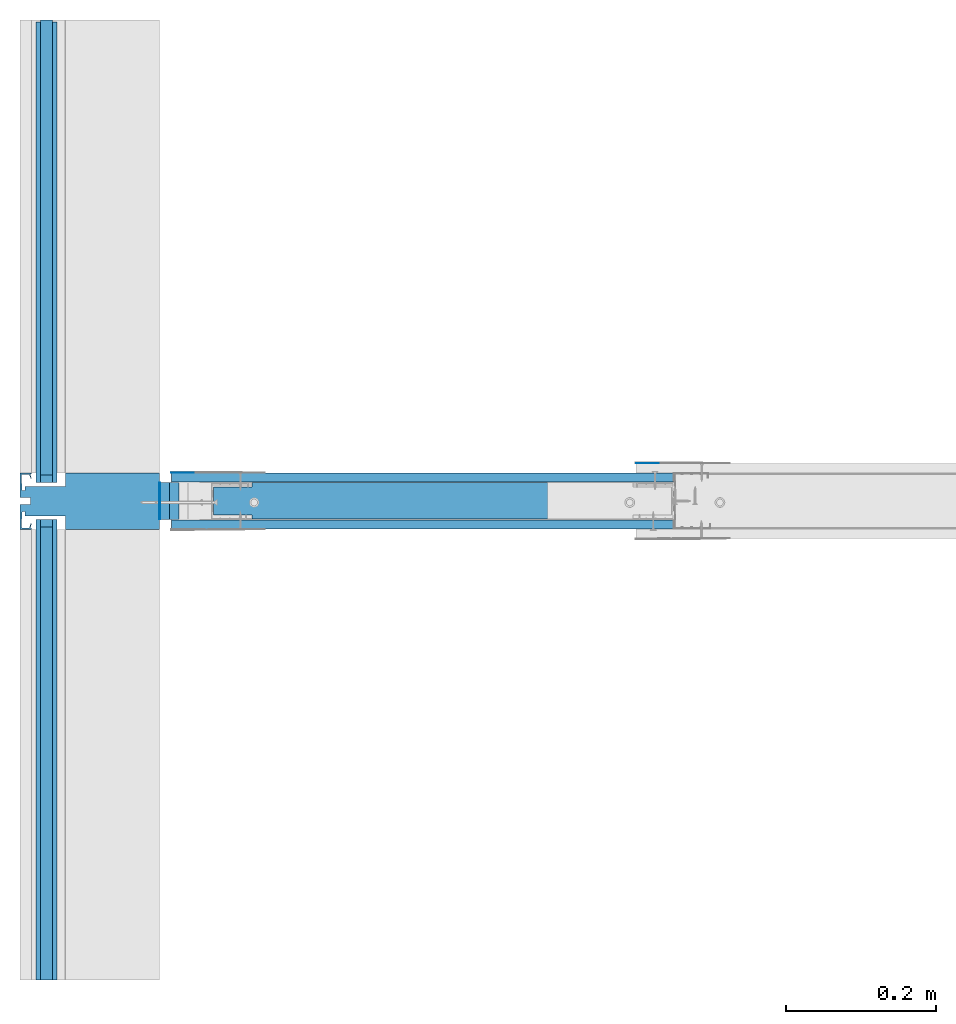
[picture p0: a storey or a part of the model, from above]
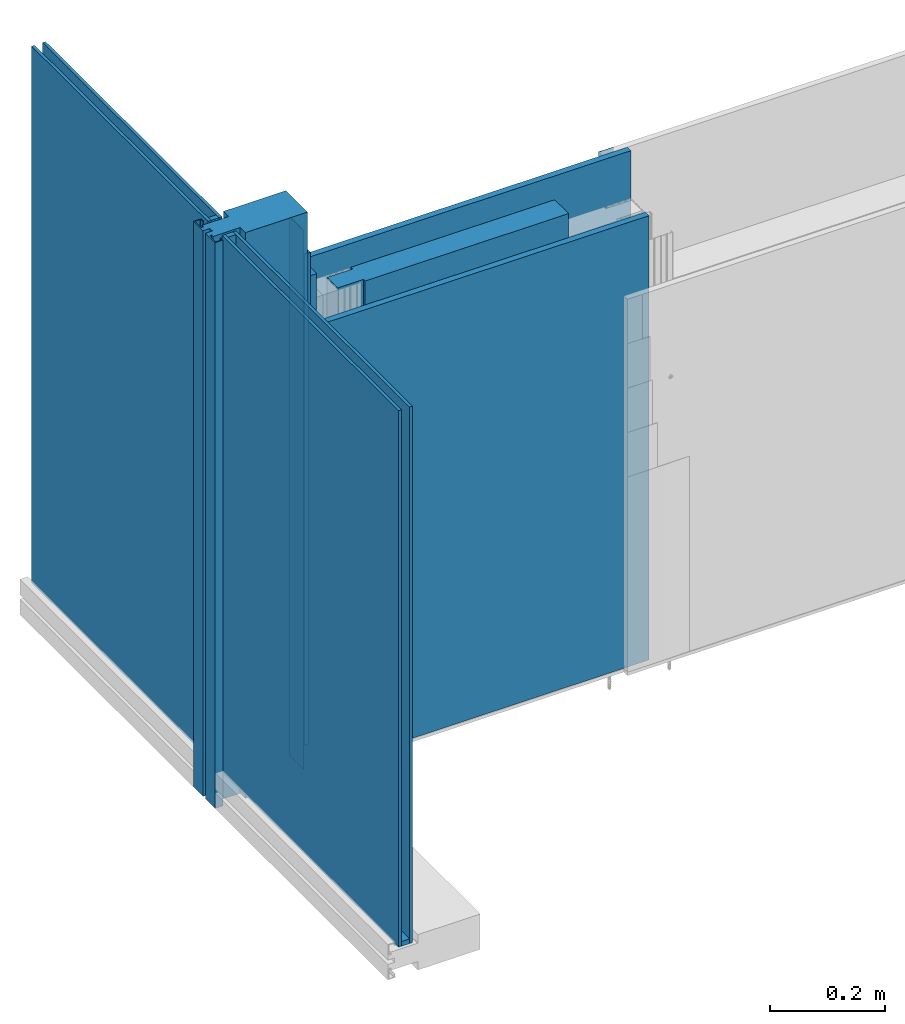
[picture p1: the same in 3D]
Properties of the parts of a building model (IFC2X3)

# File
Description: ViewDefinition [CoordinationView]
Time: 2022-01-05T15:09:06
Made in: SketchUp Pro 2015

# IfcProject, Default Project
Description: Description of Default Project

# IfcSite, Default Site
Description: Description of Default Site; RefLatitude: 24, 28, 0; RefLongitude: 54, 25, 0; RefElevation: 10 mm

# IfcBuilding, Default Building
Description: Description of Default Building

# IfcBuildingStorey, Default Building Storey
In: Default Building
Description: Description of Default Building Storey; Elevation: 0 mm

# IfcWall (97)
In: Default Building Storey
Description: Description of Object
Name
3 x Taśma uszczelniająca piankowa RIGIPS
30 x Wkręt RIGIPS TN 25
7 x Płyta gipsowo-kartonowa RIGIPS PRO (4PRO™)
2 x Profil RIGIPS CW50 ULTRASTIL®
9 x Kołek rozporowy min. fi 6
4 x Wełna mineralna szklana lub skalna ISOVER
Element mocujący
Profil RIGIPS UW 50 ULTRASTIL®
Profil RIGIPS UW75 ULTRASTIL®
9 x ELEWACJA
2 x Profil RIGIPS CW75 ULTRASTIL®
16 x Dedykowana masa szpachlowa Rigips - konstrukcyjna
4 x Taśma spoinowa RIGIPS
4 x Dedykowana masa szpachlowa Rigips - wykończeniowa
4 x Półnarożnik aluminiowy
